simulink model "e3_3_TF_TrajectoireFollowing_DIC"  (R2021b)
settings: Solver=FixedStepAuto  StartTime=0.0  StopTime=100  FixedStep=sampleTime  RelTol=1e-3  EnableMultiTasking=on
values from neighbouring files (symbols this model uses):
  g = 9.8    [startSimulation.m]    (also in StartSimulation.m; start.m)
  limit_cmd_xy = inf    [startSimulation.m]    (also in StartSimulation.m; start.m)
  saturation_psi = 2    [startSimulation.m]    (also in StartSimulation.m; start.m)
  saturation_x = 2    [startSimulation.m]    (also in StartSimulation.m; start.m)
  saturation_y = 2    [startSimulation.m]    (also in StartSimulation.m; start.m)
  saturation_z = 2    [startSimulation.m]    (also in StartSimulation.m; start.m)
  yita_x = 0.05    [startSimulation.m]    (also in StartSimulation.m; start.m)
  yita_y = 0.15    [startSimulation.m]    (also in StartSimulation.m; start.m)
libraries: simulink x12, aerolibanimutils x1

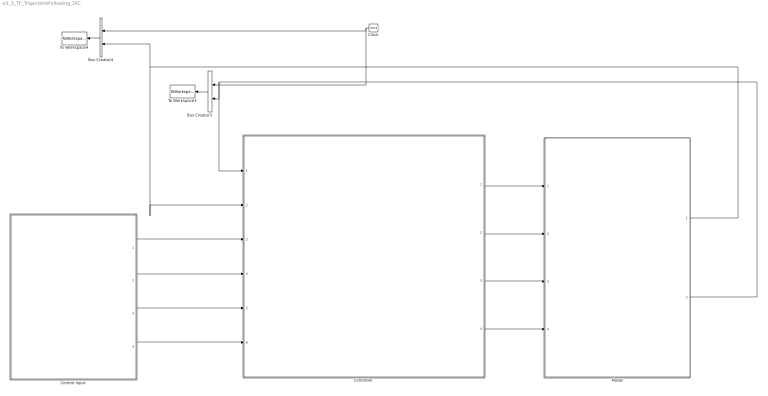
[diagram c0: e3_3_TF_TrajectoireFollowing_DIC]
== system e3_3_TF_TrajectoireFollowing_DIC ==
  Bus Creator3 : BusCreator  Inputs=2
  Bus Creator4 : BusCreator  Inputs=2
  Clock : Clock
  Control Input : Subsystem
  "Controller " : Subsystem
  Model : Subsystem
  To Workspace3 : ToWorkspace  VariableName=r1_pos_array  SampleTime=-1
  To Workspace4 : ToWorkspace  VariableName=r1_vel_array  SampleTime=-1
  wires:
  Clock/1 -> Bus Creator3/1, Bus Creator4/1
  Bus Creator3/1 -> To Workspace3/1
  Bus Creator4/1 -> To Workspace4/1
  "Controller "/1(Controller Output X) -> Model/1(Commande Input X)
  "Controller "/2(Controller Output Y) -> Model/2(Commande Input Y)
  "Controller "/3(Controller Output H) -> Model/3(Commande Input H)
  "Controller "/4(Controller Output Psi) -> Model/4(Commande Input Psi)
  Control Input/1(ux) -> "Controller "/3(Control input X)
  Control Input/2(uy) -> "Controller "/4(Control input Y)
  Control Input/3(uz) -> "Controller "/5(Control input H)
  Control Input/4(upsi) -> "Controller "/6(Control input Psi)
  Model/2(Output Position) -> "Controller "/1(Feedback Position), Bus Creator3/2
  Model/1(Output Velocity) -> "Controller "/2(Feedback Velocity), Bus Creator4/2

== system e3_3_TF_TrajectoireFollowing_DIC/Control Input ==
  Bloc Test Cercle T=10s : Subsystem
  Bloc Test Cercle T=20s : Subsystem
  Bloc Test Cercle T=5s : Subsystem
  Bus Creator1 : BusCreator  Inputs=4
  Demux : Demux
  Simulation Pace : aerolibanimutils/Simulation Pace  SimulationPace=100  SleepMode=MATLAB Thread  OutputPaceError=off  SampleTime=-1
  ux : Outport  VectorParamsAs1DForOutWhenUnconnected=off
  uy : Outport  Port=2  VectorParamsAs1DForOutWhenUnconnected=off
  uz : Outport  Port=3  VectorParamsAs1DForOutWhenUnconnected=off
  upsi : Outport  Port=4  VectorParamsAs1DForOutWhenUnconnected=off
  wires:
  Demux/2 -> uy/1
  Demux/1 -> ux/1
  Demux/3 -> uz/1
  Demux/4 -> upsi/1
  Bus Creator1/1 -> Demux/1
  Bloc Test Cercle T=20s/1(ux) -> Bus Creator1/1
  Bloc Test Cercle T=20s/2(uy) -> Bus Creator1/2
  Bloc Test Cercle T=20s/3(uz) -> Bus Creator1/3
  Bloc Test Cercle T=20s/4(upsi) -> Bus Creator1/4

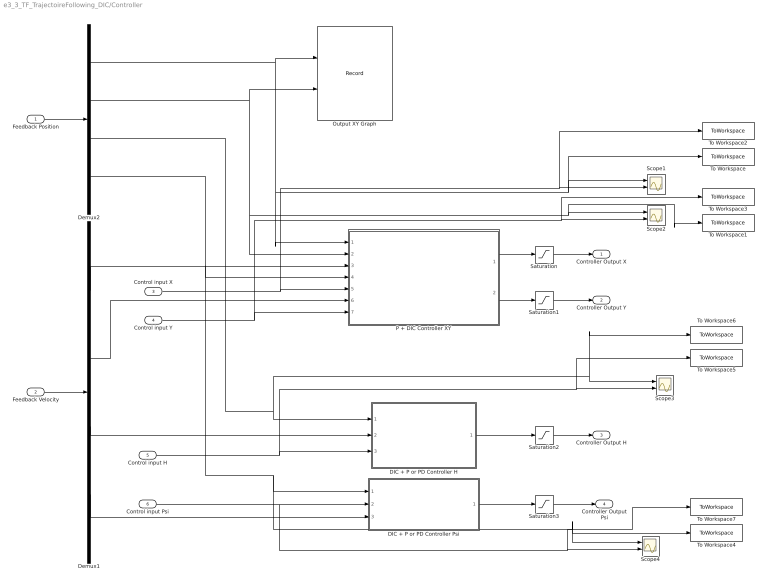
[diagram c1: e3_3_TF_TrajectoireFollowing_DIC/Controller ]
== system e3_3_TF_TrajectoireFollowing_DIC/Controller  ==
  Feedback Position : Inport
  Feedback Velocity : Inport  Port=2
  Control input X : Inport  Port=3
  Control input Y : Inport  Port=4
  Control input H : Inport  Port=5
  Control input Psi : Inport  Port=6
  DIC + P or PD Controller H : Subsystem
  DIC + P or PD Controller Psi : Subsystem
  Demux1 : Demux
  Demux2 : Demux
  Output XY Graph : Record  FileSettingsInternal="{\"entries\":[{\"content\":{\"excelSettings\":{\"content\":{},\"type\":\"Streamout.ExcelSettings\"}},\"type\":\"Streamout.FileSettingStorage\",\"uuid\":\"c88d6f4c-995e-4e1a-83da-4125e6ac1a89\"}],\"packageUris\":[\"http://schema.mathworks.com/mf0/streamout_blocks/R2020a\"],\"version\":\"1.0\"}"  Layout=[1 1]  SignalsInternal="{\"entries\":[{\"content\":{\"signals\":[{\"content\":{\"blockPath\":[\"e3_3_TF_TrajectoireFollowing_DIC/Controller /Output XY Graph\"],\"channel\":[],\"dimensions\":[1],\"domain\":\"e3_3_TF_TrajectoireFollowing_DIC/Controller /Output XY Graph\",\"lineColor\":\"#a2142f\",\"plots\":[1],\"port\":1,\"sid\":[\"\"],\"signalID\":694,\"signalName\":\"Demux2:1\"},\"type\":\"RecordBlkView.Signal\",\"uuid\":\"cc2322c7-23b0-422c-9ae1-c0d4b7496826\"},{\"c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"  VisualizationBindings="{\"xyplotplugin\":{\"info\":[{\"series\":[{\"bindingParametersList\":[{\"parameter\":\"X-Axis\",\"signalID\":694,\"signalName\":\"Demux2:1\"},{\"parameter\":\"Y-Axis\",\"signalID\":698,\"signalName\":\"Demux2:2\"}],\"seriesID\":32585}],\"subplotID\":1}]}}"  CompatibilityTag=XY  st=-1
  P + DIC Controller XY : Subsystem
  Saturation : Saturate  UpperLimit=saturation_x  LowerLimit=-saturation_x
  Saturation1 : Saturate  UpperLimit=saturation_y  LowerLimit=-saturation_y
  Saturation2 : Saturate  UpperLimit=saturation_z  LowerLimit=-saturation_z
  Saturation3 : Saturate  UpperLimit=saturation_psi  LowerLimit=-saturation_psi
  Scope{1..4} (4 alike) : Scope  NumInputPorts=2
  To Workspace : ToWorkspace  VariableName=N4_Step3_Out_X  SampleTime=-1
  To Workspace1 : ToWorkspace  VariableName=N4_Step3_Out_Y  SampleTime=-1
  To Workspace2 : ToWorkspace  VariableName=N4_Step3_In_X  SampleTime=-1
  To Workspace3 : ToWorkspace  VariableName=N4_Step3_In_Y  SampleTime=-1
  To Workspace4 : ToWorkspace  VariableName=N4_Step3_Out_Psi  SampleTime=-1
  To Workspace5 : ToWorkspace  VariableName=N4_Step3_In_H  SampleTime=-1
  To Workspace6 : ToWorkspace  VariableName=N4_Step3_Out_H  SampleTime=-1
  To Workspace7 : ToWorkspace  VariableName=N4_Step3_In_Psi  SampleTime=-1
  Controller Output X : Outport  VectorParamsAs1DForOutWhenUnconnected=off
  Controller Output Y : Outport  Port=2  VectorParamsAs1DForOutWhenUnconnected=off
  Controller Output H : Outport  Port=3  VectorParamsAs1DForOutWhenUnconnected=off
  Controller Output Psi : Outport  Port=4  VectorParamsAs1DForOutWhenUnconnected=off
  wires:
  Feedback Position/1 -> Demux2/1
  Feedback Velocity/1 -> Demux1/1
  Demux2/3 -> DIC + P or PD Controller H/1(Feedback Position H), Scope3/1, To Workspace6/1
  Demux1/3 -> DIC + P or PD Controller H/2(Feedback Velocity H)
  Control input Psi/1 -> DIC + P or PD Controller Psi/2(Control input Psi), Scope4/2, To Workspace7/1
  Control input H/1 -> DIC + P or PD Controller H/3(Control Input H), Scope3/2, To Workspace5/1
  Saturation/1 -> Controller Output X/1
  Saturation1/1 -> Controller Output Y/1
  Saturation2/1 -> Controller Output H/1
  Saturation3/1 -> Controller Output Psi/1
  DIC + P or PD Controller H/1(Controller Output H) -> Saturation2/1
  DIC + P or PD Controller Psi/1(Controller Output Psi) -> Saturation3/1
  Demux2/1 -> P + DIC Controller XY/1(Feedback Position X), To Workspace/1, Scope1/1, Output XY Graph/1
  Demux2/2 -> P + DIC Controller XY/2(Feedback Position Y), To Workspace1/1, Scope2/1, Output XY Graph/2
  Demux2/4 -> DIC + P or PD Controller Psi/1(Feedback Position Psi), Scope4/1, To Workspace4/1, P + DIC Controller XY/4(Feedback Position Psi)
  Control input X/1 -> To Workspace2/1, Scope1/2, P + DIC Controller XY/5(Control input Position X)
  Control input Y/1 -> P + DIC Controller XY/7(Control input Position Y), Scope2/2, To Workspace3/1
  Demux1/1 -> P + DIC Controller XY/3(Feedback Velocity X)
  Demux1/2 -> P + DIC Controller XY/6(Feedback Velocity Y)
  P + DIC Controller XY/1(Controller Output X) -> Saturation/1
  P + DIC Controller XY/2(Controller Output Y) -> Saturation1/1
  Demux1/4 -> DIC + P or PD Controller Psi/3(Feedback Velocity Psi)

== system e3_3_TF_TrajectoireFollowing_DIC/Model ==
  Commande Input X : Inport
  Commande Input Y : Inport  Port=2
  Commande Input H : Inport  Port=3
  Commande Input Psi : Inport  Port=4
  Step2_Model : Subsystem
  Output Velocity : Outport  VectorParamsAs1DForOutWhenUnconnected=off
  Output Position : Outport  Port=2  VectorParamsAs1DForOutWhenUnconnected=off
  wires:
  Commande Input Y/1 -> Step2_Model/2(In2)
  Commande Input Psi/1 -> Step2_Model/4(In4)
  Commande Input H/1 -> Step2_Model/3(In3)
  Step2_Model/1(Position) -> Output Position/1
  Commande Input X/1 -> Step2_Model/1(In1)
  Step2_Model/2(Velocity) -> Output Velocity/1

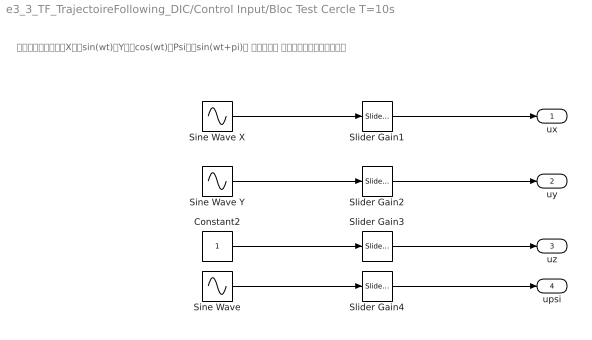
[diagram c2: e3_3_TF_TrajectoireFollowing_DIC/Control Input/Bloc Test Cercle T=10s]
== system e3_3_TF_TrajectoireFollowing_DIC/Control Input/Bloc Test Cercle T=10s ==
  note: 机头指向圆心飞圆，X通道sin(wt)，Y通道cos(wt)，Psi通道sin(wt+pi)。 三者的周期 需要一致才能达到此效果。
  Constant2 : Constant
  Sine Wave : Sin  Frequency=0.65  Phase=pi  SampleTime=0
  Sine Wave X : Sin  Frequency=0.65  SampleTime=0
  Sine Wave Y : Sin  Frequency=0.65  Phase=pi/2  SampleTime=0
  Slider Gain1 : simulink/Math Operations/Slider Gain  gain=1  low=-10  high=10
  Slider Gain2 : simulink/Math Operations/Slider Gain  gain=1  low=-10  high=10
  Slider Gain3 : simulink/Math Operations/Slider Gain  gain=2  low=-2  high=2
  Slider Gain4 : simulink/Math Operations/Slider Gain  gain=1  low=-2  high=2
  ux : Outport  VectorParamsAs1DForOutWhenUnconnected=off
  uy : Outport  Port=2  VectorParamsAs1DForOutWhenUnconnected=off
  uz : Outport  Port=3  VectorParamsAs1DForOutWhenUnconnected=off
  upsi : Outport  Port=4  VectorParamsAs1DForOutWhenUnconnected=off
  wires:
  Slider Gain2/1 -> uy/1
  Slider Gain3/1 -> uz/1
  Slider Gain4/1 -> upsi/1
  Slider Gain1/1 -> ux/1
  Constant2/1 -> Slider Gain3/1
  Sine Wave/1 -> Slider Gain4/1
  Sine Wave X/1 -> Slider Gain1/1
  Sine Wave Y/1 -> Slider Gain2/1

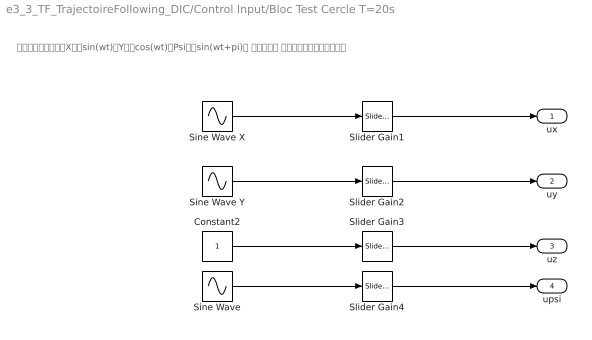
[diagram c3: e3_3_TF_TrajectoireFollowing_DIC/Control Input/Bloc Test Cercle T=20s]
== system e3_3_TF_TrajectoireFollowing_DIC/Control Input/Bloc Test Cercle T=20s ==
  note: 机头指向圆心飞圆，X通道sin(wt)，Y通道cos(wt)，Psi通道sin(wt+pi)。 三者的周期 需要一致才能达到此效果。
  Constant2 : Constant
  Sine Wave : Sin  Frequency=0.35  Phase=pi  SampleTime=0
  Sine Wave X : Sin  Frequency=0.35  SampleTime=0
  Sine Wave Y : Sin  Frequency=0.35  Phase=pi/2  SampleTime=0
  Slider Gain1 : simulink/Math Operations/Slider Gain  gain=1  low=-10  high=10
  Slider Gain2 : simulink/Math Operations/Slider Gain  gain=1  low=-10  high=10
  Slider Gain3 : simulink/Math Operations/Slider Gain  gain=2  low=-2  high=2
  Slider Gain4 : simulink/Math Operations/Slider Gain  gain=1  low=-2  high=2
  ux : Outport  VectorParamsAs1DForOutWhenUnconnected=off
  uy : Outport  Port=2  VectorParamsAs1DForOutWhenUnconnected=off
  uz : Outport  Port=3  VectorParamsAs1DForOutWhenUnconnected=off
  upsi : Outport  Port=4  VectorParamsAs1DForOutWhenUnconnected=off
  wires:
  Slider Gain2/1 -> uy/1
  Slider Gain3/1 -> uz/1
  Slider Gain4/1 -> upsi/1
  Slider Gain1/1 -> ux/1
  Constant2/1 -> Slider Gain3/1
  Sine Wave/1 -> Slider Gain4/1
  Sine Wave X/1 -> Slider Gain1/1
  Sine Wave Y/1 -> Slider Gain2/1

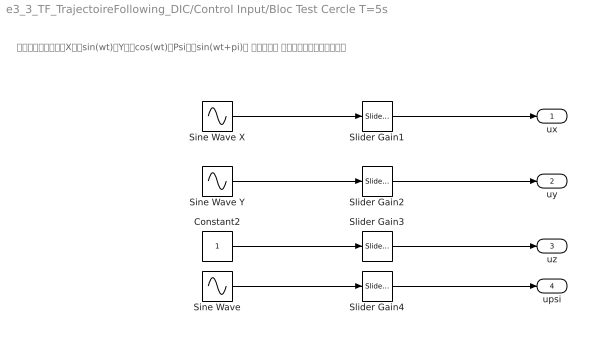
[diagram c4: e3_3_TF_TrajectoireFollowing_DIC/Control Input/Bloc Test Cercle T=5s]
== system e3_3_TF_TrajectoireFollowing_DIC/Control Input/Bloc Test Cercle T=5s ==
  note: 机头指向圆心飞圆，X通道sin(wt)，Y通道cos(wt)，Psi通道sin(wt+pi)。 三者的周期 需要一致才能达到此效果。
  Constant2 : Constant
  Sine Wave : Sin  Phase=pi  SampleTime=0
  Sine Wave X : Sin  SampleTime=0
  Sine Wave Y : Sin  Phase=pi/2  SampleTime=0
  Slider Gain1 : simulink/Math Operations/Slider Gain  gain=1  low=-10  high=10
  Slider Gain2 : simulink/Math Operations/Slider Gain  gain=1  low=-10  high=10
  Slider Gain3 : simulink/Math Operations/Slider Gain  gain=2  low=-2  high=2
  Slider Gain4 : simulink/Math Operations/Slider Gain  gain=1  low=-2  high=2
  ux : Outport  VectorParamsAs1DForOutWhenUnconnected=off
  uy : Outport  Port=2  VectorParamsAs1DForOutWhenUnconnected=off
  uz : Outport  Port=3  VectorParamsAs1DForOutWhenUnconnected=off
  upsi : Outport  Port=4  VectorParamsAs1DForOutWhenUnconnected=off
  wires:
  Slider Gain2/1 -> uy/1
  Slider Gain3/1 -> uz/1
  Slider Gain4/1 -> upsi/1
  Slider Gain1/1 -> ux/1
  Constant2/1 -> Slider Gain3/1
  Sine Wave/1 -> Slider Gain4/1
  Sine Wave X/1 -> Slider Gain1/1
  Sine Wave Y/1 -> Slider Gain2/1

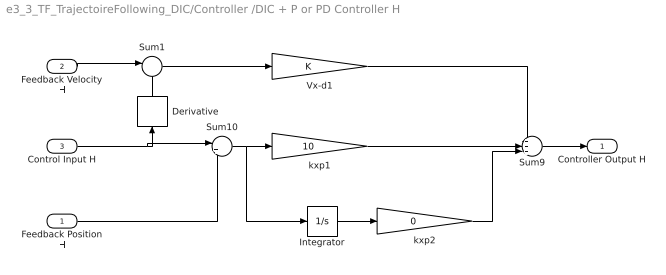
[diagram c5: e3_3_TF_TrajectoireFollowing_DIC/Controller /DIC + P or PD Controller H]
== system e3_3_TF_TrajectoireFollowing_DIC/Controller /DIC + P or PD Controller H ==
  Feedback Position H : Inport
  Feedback Velocity H : Inport  Port=2
  Control Input H : Inport  Port=3
  Derivative : Derivative
  Integrator : Integrator
  Sum1 : Sum  Inputs=|-+
  Sum10 : Sum  Inputs=|+-
  Sum9 : Sum  Inputs=+++|
  Vx-d1 : Gain
  kxp1 : Gain  Gain=10
  kxp2 : Gain  Gain=0
  Controller Output H : Outport  VectorParamsAs1DForOutWhenUnconnected=off
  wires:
  Sum9/1 -> Controller Output H/1
  Sum10/1 -> Integrator/1, kxp1/1
  kxp1/1 -> Sum9/2
  Vx-d1/1 -> Sum9/1
  Feedback Velocity H/1 -> Sum1/1
  Sum1/1 -> Vx-d1/1
  Integrator/1 -> kxp2/1
  kxp2/1 -> Sum9/3
  Control Input H/1 -> Sum10/1, Derivative/1
  Feedback Position H/1 -> Sum10/2
  Derivative/1 -> Sum1/2

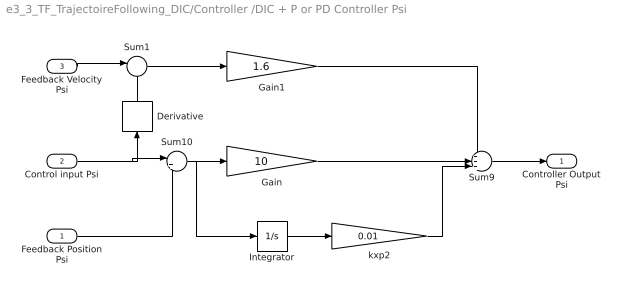
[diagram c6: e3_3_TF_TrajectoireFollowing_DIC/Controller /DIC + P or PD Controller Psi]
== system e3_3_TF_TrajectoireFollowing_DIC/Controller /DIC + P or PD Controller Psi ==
  Feedback Position Psi : Inport
  Control input Psi : Inport  Port=2
  Feedback Velocity Psi : Inport  Port=3
  Derivative : Derivative
  Gain : Gain  Gain=10
  Gain1 : Gain  Gain=1.6
  Integrator : Integrator
  Sum1 : Sum  Inputs=|-+
  Sum10 : Sum  Inputs=|+-
  Sum9 : Sum  Inputs=+++|
  kxp2 : Gain  Gain=0.01
  Controller Output Psi : Outport  VectorParamsAs1DForOutWhenUnconnected=off
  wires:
  Sum9/1 -> Controller Output Psi/1
  kxp2/1 -> Sum9/3
  Control input Psi/1 -> Sum10/1, Derivative/1
  Gain1/1 -> Sum9/1
  Sum10/1 -> Gain/1, Integrator/1
  Integrator/1 -> kxp2/1
  Feedback Velocity Psi/1 -> Sum1/1
  Sum1/1 -> Gain1/1
  Gain/1 -> Sum9/2
  Derivative/1 -> Sum1/2
  Feedback Position Psi/1 -> Sum10/2

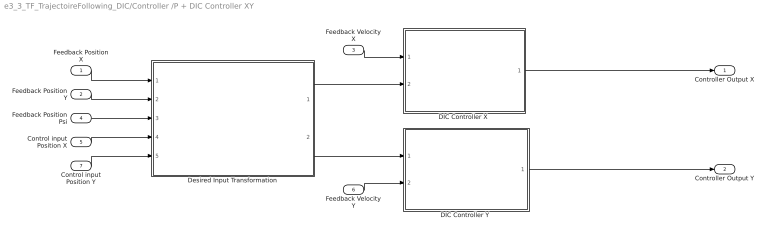
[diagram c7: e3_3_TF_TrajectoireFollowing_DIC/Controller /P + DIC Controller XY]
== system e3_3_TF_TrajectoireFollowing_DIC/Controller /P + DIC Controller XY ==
  Feedback Position X : Inport
  Feedback Position Y : Inport  Port=2
  Feedback Velocity X : Inport  Port=3
  Feedback Position Psi : Inport  Port=4
  Control input Position X : Inport  Port=5
  Feedback Velocity Y : Inport  Port=6
  Control input Position Y : Inport  Port=7
  "DIC Controller X " : Subsystem
  "DIC Controller Y " : Subsystem
  Desired Input Transformation : Subsystem
  Controller Output X : Outport  VectorParamsAs1DForOutWhenUnconnected=off
  Controller Output Y : Outport  Port=2  VectorParamsAs1DForOutWhenUnconnected=off
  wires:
  Feedback Velocity X/1 -> "DIC Controller X "/1(Feedback Velocity X)
  Feedback Velocity Y/1 -> "DIC Controller Y "/2(Feedback Velocity Y)
  Desired Input Transformation/1(v_hb_dx) -> "DIC Controller X "/2(Control Input X)
  Desired Input Transformation/2(v_hb_dy) -> "DIC Controller Y "/1(Control Input Y)
  Feedback Position Psi/1 -> Desired Input Transformation/3(" Feedback Position Psi")
  Control input Position Y/1 -> Desired Input Transformation/5(Control input Position Y)
  Feedback Position X/1 -> Desired Input Transformation/1(Feedback Position X)
  Control input Position X/1 -> Desired Input Transformation/4(Control input Position X)
  Feedback Position Y/1 -> Desired Input Transformation/2(Feedback Position Y)
  "DIC Controller X "/1(Controller Output X) -> Controller Output X/1
  "DIC Controller Y "/1(Controller Output Y) -> Controller Output Y/1

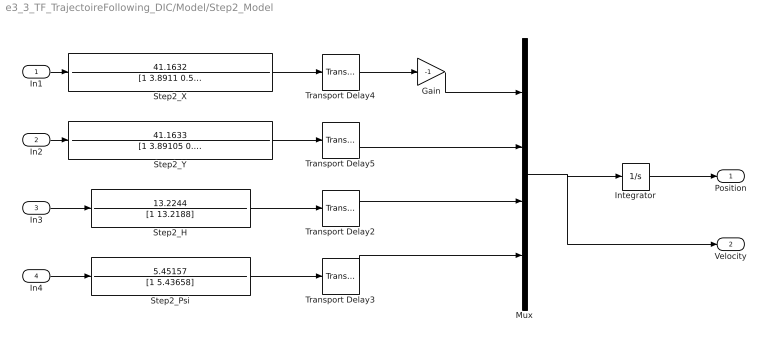
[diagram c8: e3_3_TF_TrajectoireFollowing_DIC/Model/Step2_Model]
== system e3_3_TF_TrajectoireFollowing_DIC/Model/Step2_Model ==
  In1 : Inport
  In2 : Inport  Port=2
  In3 : Inport  Port=3
  In4 : Inport  Port=4
  Gain : Gain  Gain=-1
  Integrator : Integrator
  Mux : Mux
  Step2_H : TransferFcn  Numerator=13.2244  Denominator=[1 13.2188]
  Step2_Psi : TransferFcn  Numerator=5.45157  Denominator=[1 5.43658]
  Step2_X : TransferFcn  Numerator=41.1632  Denominator=[1 3.8911 0.529635]
  Step2_Y : TransferFcn  Numerator=41.1633  Denominator=[1 3.89105 0.529839]
  Transport Delay2 : TransportDelay  DelayTime=0.0344
  Transport Delay3 : TransportDelay  DelayTime=0.0313
  Transport Delay4 : TransportDelay  DelayTime=0.0289
  Transport Delay5 : TransportDelay  DelayTime=0.0289
  Position : Outport  VectorParamsAs1DForOutWhenUnconnected=off
  Velocity : Outport  Port=2  VectorParamsAs1DForOutWhenUnconnected=off
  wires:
  Transport Delay2/1 -> Mux/3
  In2/1 -> Step2_Y/1
  In4/1 -> Step2_Psi/1
  Transport Delay3/1 -> Mux/4
  In1/1 -> Step2_X/1
  In3/1 -> Step2_H/1
  Step2_H/1 -> Transport Delay2/1
  Step2_Y/1 -> Transport Delay5/1
  Step2_X/1 -> Transport Delay4/1
  Step2_Psi/1 -> Transport Delay3/1
  Transport Delay4/1 -> Gain/1
  Transport Delay5/1 -> Mux/2
  Integrator/1 -> Position/1
  Mux/1 -> Velocity/1, Integrator/1
  Gain/1 -> Mux/1

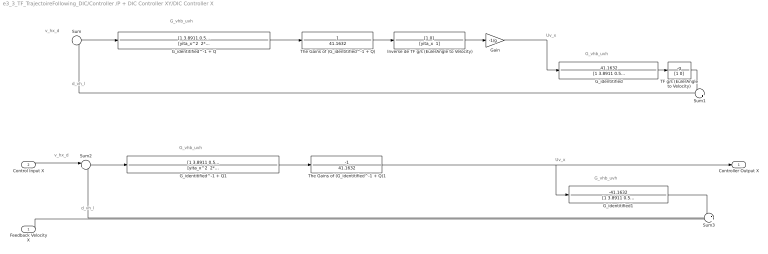
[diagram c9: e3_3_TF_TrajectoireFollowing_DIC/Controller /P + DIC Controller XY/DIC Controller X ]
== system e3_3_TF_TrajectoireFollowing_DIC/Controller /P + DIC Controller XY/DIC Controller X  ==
  note: Uv_x
  note: v_hx_d
  note: G_vhb_uvh
  note: d_vh_l
  note: G_vhb_uvh
  note: G_vhb_uvh
  note: Uv_x
  note: G_vhb_uvh
  note: d_vh_l
  note: v_hx_d
  Feedback Velocity X : Inport
  Control Input X : Inport  Port=2
  G_identitified : TransferFcn  Numerator=41.1632  Denominator=[1 3.8911 0.529635]
  G_identitified1 : TransferFcn  Numerator=-41.1632  Denominator=[1 3.8911 0.529635]
  G_identitified^-1 + Q : TransferFcn  Numerator=[1 3.8911 0.529635]  Denominator="[yita_x^2  2*yita_x  1]"
  G_identitified^-1 + Q1 : TransferFcn  Numerator=[1 3.8911 0.529635]  Denominator="[yita_x^2  2*yita_x  1]"
  Gain : Gain  Gain=-1/g
  Inverse de TF g/s (EulerAngle to Velocity) : TransferFcn  Numerator=[1 0]  Denominator="[yita_x  1]"
  Sum : Sum  Inputs=|+-
  Sum1 : Sum  Inputs=-|+
  Sum2 : Sum  Inputs=|+-
  Sum3 : Sum  Inputs=-|+
  TF g/s (EulerAngle to Velocity) : TransferFcn  Numerator=-g  Denominator=[1 0]
  The Gains of (G_identitified^-1 + Q) : TransferFcn  Numerator=1  Denominator=41.1632
  The Gains of (G_identitified^-1 + Q)1 : TransferFcn  Numerator=-1  Denominator=41.1632
  Controller Output X : Outport  VectorParamsAs1DForOutWhenUnconnected=off
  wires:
  G_identitified^-1 + Q1/1 -> The Gains of (G_identitified^-1 + Q)1/1
  G_identitified1/1 -> Sum3/1
  Feedback Velocity X/1 -> Sum3/2
  Sum2/1 -> G_identitified^-1 + Q1/1
  Control Input X/1 -> Sum2/1
  Sum3/1 -> Sum2/2
  The Gains of (G_identitified^-1 + Q)1/1 -> Controller Output X/1, G_identitified1/1
  Sum1/1 -> Sum/2
  Gain/1 -> G_identitified/1
  G_identitified/1 -> TF g/s (EulerAngle to Velocity)/1
  Sum/1 -> G_identitified^-1 + Q/1
  Inverse de TF g/s (EulerAngle to Velocity)/1 -> Gain/1
  The Gains of (G_identitified^-1 + Q)/1 -> Inverse de TF g/s (EulerAngle to Velocity)/1
  ? -> Sum/1
  G_identitified^-1 + Q/1 -> The Gains of (G_identitified^-1 + Q)/1
  TF g/s (EulerAngle to Velocity)/1 -> Sum1/1
  ? -> Sum1/2

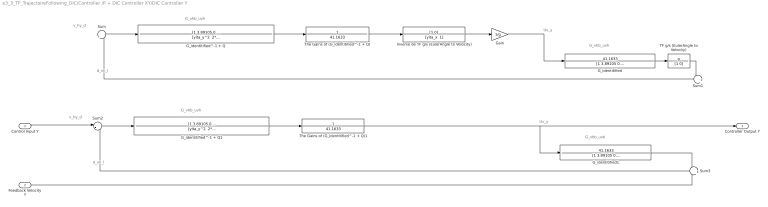
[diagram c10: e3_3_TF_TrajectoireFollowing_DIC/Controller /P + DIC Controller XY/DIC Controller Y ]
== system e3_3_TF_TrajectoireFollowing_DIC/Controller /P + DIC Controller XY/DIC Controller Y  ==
  note: G_vhb_uvh
  note: d_vh_l
  note: Uv_y
  note: G_vhb_uvh
  note: v_hy_d
  note: G_vhb_uvh
  note: d_vh_l
  note: Uv_y
  note: G_vhb_uvh
  note: v_hy_d
  Control Input Y : Inport
  Feedback Velocity Y : Inport  Port=2
  G_identitified : TransferFcn  Numerator=41.1633  Denominator=[1 3.89105 0.529839]
  G_identitified1 : TransferFcn  Numerator=41.1633  Denominator=[1 3.89105 0.529839]
  G_identitified^-1 + Q : TransferFcn  Numerator=[1 3.89105 0.529839]  Denominator="[yita_y^2  2*yita_y  1]"
  G_identitified^-1 + Q1 : TransferFcn  Numerator=[1 3.89105 0.529839]  Denominator="[yita_y^2  2*yita_y  1]"
  Gain : Gain  Gain=1/g
  Inverse de TF g/s (EulerAngle to Velocity) : TransferFcn  Numerator=[1 0]  Denominator="[yita_x  1]"
  Sum : Sum  Inputs=|+-
  Sum1 : Sum  Inputs=-|+
  Sum2 : Sum  Inputs=|+-
  Sum3 : Sum  Inputs=-|+
  TF g/s (EulerAngle to Velocity) : TransferFcn  Numerator=g  Denominator=[1 0]
  The Gains of (G_identitified^-1 + Q) : TransferFcn  Numerator=1  Denominator=41.1633
  The Gains of (G_identitified^-1 + Q)1 : TransferFcn  Numerator=1  Denominator=41.1633
  Controller Output Y : Outport  VectorParamsAs1DForOutWhenUnconnected=off
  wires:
  ? -> Sum1/2
  The Gains of (G_identitified^-1 + Q)/1 -> Inverse de TF g/s (EulerAngle to Velocity)/1
  Inverse de TF g/s (EulerAngle to Velocity)/1 -> Gain/1
  G_identitified/1 -> TF g/s (EulerAngle to Velocity)/1
  Sum1/1 -> Sum/2
  TF g/s (EulerAngle to Velocity)/1 -> Sum1/1
  Gain/1 -> G_identitified/1
  Sum/1 -> G_identitified^-1 + Q/1
  G_identitified^-1 + Q/1 -> The Gains of (G_identitified^-1 + Q)/1
  ? -> Sum/1
  Feedback Velocity Y/1 -> Sum3/2
  Sum3/1 -> Sum2/2
  G_identitified1/1 -> Sum3/1
  The Gains of (G_identitified^-1 + Q)1/1 -> Controller Output Y/1, G_identitified1/1
  Sum2/1 -> G_identitified^-1 + Q1/1
  G_identitified^-1 + Q1/1 -> The Gains of (G_identitified^-1 + Q)1/1
  Control Input Y/1 -> Sum2/1

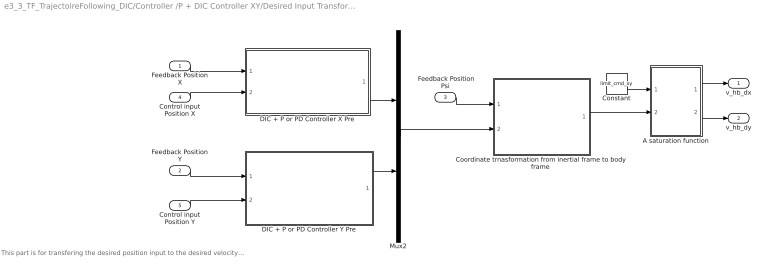
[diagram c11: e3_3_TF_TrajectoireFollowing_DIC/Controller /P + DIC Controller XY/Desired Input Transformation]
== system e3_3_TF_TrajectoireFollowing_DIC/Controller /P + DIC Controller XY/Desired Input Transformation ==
  note: This part is for transfering the desired position input to the desired velocity input, here, we add the position XY feedback for P controller, then we add the Raw feedback for a rotation of raw at the same time.
  Feedback Position X : Inport
  Feedback Position Y : Inport  Port=2
  " Feedback Position Psi" : Inport  Port=3
  Control input Position X : Inport  Port=4
  Control input Position Y : Inport  Port=5
  A saturation function : MATLAB Function  TreatAsAtomicUnit=on
  Constant : Constant  Value=limit_cmd_xy
  "Coordinate trnasformation from inertial frame to body frame " : MATLAB Function  TreatAsAtomicUnit=on
  DIC + P or PD Controller X Pre : Subsystem
  DIC + P or PD Controller Y Pre : Subsystem
  Mux2 : Mux  Inputs=2
  v_hb_dx : Outport  VectorParamsAs1DForOutWhenUnconnected=off
  v_hb_dy : Outport  Port=2  VectorParamsAs1DForOutWhenUnconnected=off
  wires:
  " Feedback Position Psi"/1 -> "Coordinate trnasformation from inertial frame to body frame "/1(psi)
  Feedback Position Y/1 -> DIC + P or PD Controller Y Pre/1(Feedback Position Y)
  Feedback Position X/1 -> DIC + P or PD Controller X Pre/1(Feedback Position X)
  Control input Position X/1 -> DIC + P or PD Controller X Pre/2(Control Input X)
  Control input Position Y/1 -> DIC + P or PD Controller Y Pre/2(Control Input Y)
  Mux2/1 -> "Coordinate trnasformation from inertial frame to body frame "/2(Vec_i)
  DIC + P or PD Controller X Pre/1(Controller Output v_x) -> Mux2/1
  Constant/1 -> A saturation function/1(a)
  "Coordinate trnasformation from inertial frame to body frame "/1(Vec_xy) -> A saturation function/2(u)
  DIC + P or PD Controller Y Pre/1(Controller Output v_y) -> Mux2/2
  A saturation function/2(outy) -> v_hb_dy/1
  A saturation function/1(outx) -> v_hb_dx/1

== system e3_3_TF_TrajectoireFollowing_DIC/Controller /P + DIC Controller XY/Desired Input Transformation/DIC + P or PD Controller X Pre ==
  Feedback Position X : Inport
  Control Input X : Inport  Port=2
  Gain_Kph_X : Gain  Gain=5
  Sum1 : Sum  Inputs=-+|
  Controller Output v_x : Outport  VectorParamsAs1DForOutWhenUnconnected=off
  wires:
  Feedback Position X/1 -> Sum1/1
  Control Input X/1 -> Sum1/2
  Sum1/1 -> Gain_Kph_X/1
  Gain_Kph_X/1 -> Controller Output v_x/1

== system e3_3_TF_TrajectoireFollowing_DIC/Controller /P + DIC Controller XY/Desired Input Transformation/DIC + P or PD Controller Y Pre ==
  Feedback Position Y : Inport
  Control Input Y : Inport  Port=2
  Gain_Kph_Y : Gain  Gain=3
  Sum1 : Sum  Inputs=-+|
  Controller Output v_y : Outport  VectorParamsAs1DForOutWhenUnconnected=off
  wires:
  Feedback Position Y/1 -> Sum1/1
  Control Input Y/1 -> Sum1/2
  Sum1/1 -> Gain_Kph_Y/1
  Gain_Kph_Y/1 -> Controller Output v_y/1

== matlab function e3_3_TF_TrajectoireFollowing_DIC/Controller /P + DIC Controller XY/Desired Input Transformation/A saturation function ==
function [outx,outy] = fcn(a, u)
    temp = norm(u,Inf);
    if  temp<=a
        outx = u(1);
        outy = u(2);
    else
        outx = (a/temp)*u(1);
        outy = (a/temp)*u(2);
    end
end

== matlab function e3_3_TF_TrajectoireFollowing_DIC/Controller /P + DIC Controller XY/Desired Input Transformation/Coordinate trnasformation 
from inertial frame to body frame  ==
function Vec_xy  = fcn( psi,Vec_i )
%#codegen
T = [cos(psi) -sin(psi) ; sin(psi) cos(psi)] ; % Rpsi
Kph=eye(2); % the parameters of P controller
% Vec_xy = inv(T)*Kph*Vec_i(1:2,1); 
Vec_xy = inv(T)*Vec_i(1:2,1);
